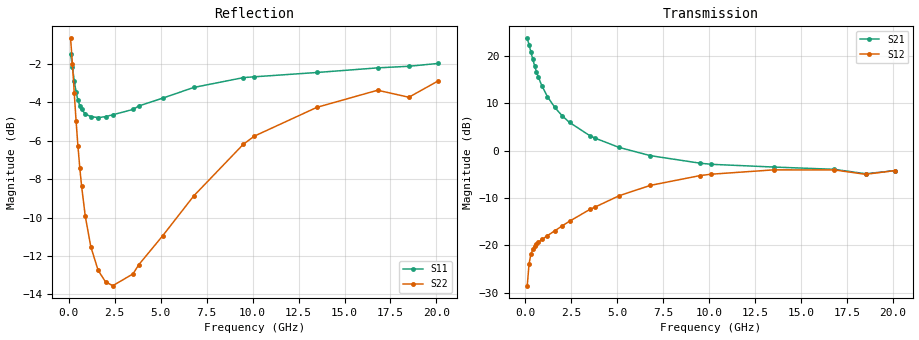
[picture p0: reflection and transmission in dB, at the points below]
!  Infineon Technologies AG
! BFR380L3 , PF131585-7, No.6, Th 09.10.01, soldered on pcb-board, measured with PP GSG850
!  Vce=0.75 V,  Ic=5.0 mA
! Common Emitter S-Parameters:  15. November 2001
#  GHz  S  MA  R  50
! f  S11  S21  S12  S22
! GHz  Mag  Ang  Mag  Ang  Mag  Ang  Mag  Ang
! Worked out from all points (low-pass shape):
!   201 points, 100 MHz to 20.1 GHz, reference 50 ohm
!   highest |S21| = 23.72 dB at 100 MHz (marker M1); lowest = -4.9 dB at 18.5 GHz (marker M2)
!   |S21| within 3 dB of the highest: start of sweep to 306.9 MHz
!   lowest |S11| = -4.8 dB at 1.6 GHz (marker M3), VSWR 3.72, Z = 13.4 - j1.02 ohm
!   |S11| at or under -10 dB: nowhere
!   |S22| runs from -13.5 to -0.7 dB; largest |S21 - S12| = 15
!   S11 on the Smith chart (normalised r, x): 100 MHz: 0.92, -3.02; 400 MHz: 0.31, -0.74; 900 MHz: 0.28, -0.25; 3.8 GHz: 0.27, +0.34; 9.5 GHz: 0.36, +1.11; 20.1 GHz: 0.94, +2.56
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0.1  0.8445 -33.9  15.34 158.1  0.0374 72.2  0.9268 -23.1
0.2  0.7814 -63.4  13.12 140.4  0.06402 58.9  0.7963 -41.6
0.3  0.7183 -86.1  10.99 127.5  0.08032 49.6  0.6676 -55.2
0.4  0.6721 -103.4  9.236 117.9  0.09033 44.3  0.5635 -65.4
0.5  0.6396 -117.0  7.873 110.5  0.0974 41.3  0.4854 -73.4
0.6  0.619 -127.7  6.818 104.8  0.1027 39.4  0.4268 -79.7
0.7  0.6052 -136.4  6.003 99.9  0.1073 38.4  0.3815 -85.1
0.9  0.5885 -149.6  4.817 92.4  0.1151 38.2  0.3188 -94.0
1.2  0.5795 -164.0  3.715 83.5  0.1264 39.3  0.2656 -104.4
1.6  0.5762 -177.5  2.857 74.1  0.1423 41.6  0.2304 -115.8
2  0.5795 172.2  2.332 66.2  0.16 43.5  0.2151 -125.1
2.4  0.5861 163.6  1.985 59.1  0.1795 44.9  0.2102 -133.4
3.5  0.6052 144.2  1.439 42.5  0.2387 45.6  0.2257 -151.8
3.8  0.6175 140.0  1.352 38.8  0.2539 45.0  0.2381 -157.4
5.1  0.6473 122.3  1.08 23.7  0.3337 40.2  0.2832 -175.8
6.8  0.6904 103.3  0.8842 9.4  0.4293 30.9  0.3602 160.9
9.5  0.7324 80.8  0.7364 -5.6  0.5446 13.4  0.4912 131.7
10.1  0.736 76.8  0.7167 -7.9  0.5632 9.6  0.5157 125.4
13.5  0.7552 58.8  0.6705 -21.9  0.6259 -11.5  0.6128 96.3
16.8  0.7765 47.0  0.6345 -33.0  0.6247 -27.1  0.679 75.1
18.5  0.7839 45.2  0.5694 -40.6  0.5618 -35.5  0.651 69.9
20.1  0.7975 38.5  0.6138 -43.9  0.6152 -40.3  0.7182 59.3
